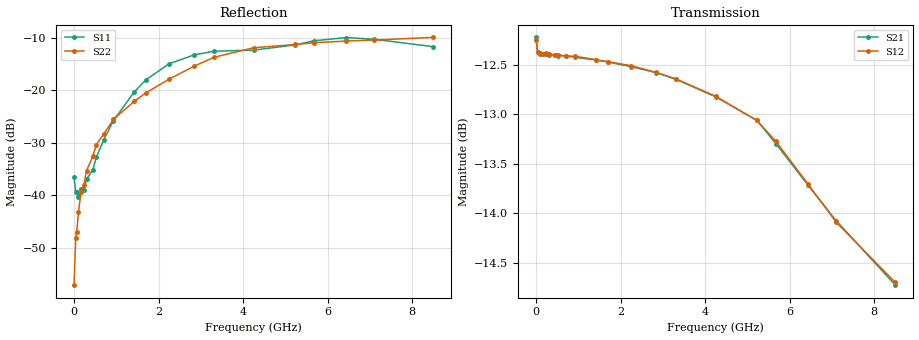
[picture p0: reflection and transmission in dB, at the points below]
! device id: pe43620
! dir: c:\dsa\pe43620\data\pe43620\085c\3p300v\12p00db
! Serial: 1001
! Insertion: A
! Temp: 85C
! VDD: 3.300V
! Attenuation Step: 12.00dB
! IDD: 1.066358e-02mA
! FILE NAME
! DATE 10-22-2008 15:09:18
! CORRECTED  DATA
#  Hz  S  RI  R  50.00
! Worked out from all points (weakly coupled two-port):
!   401 points, 300 kHz to 8.5 GHz, reference 50 ohm
!   highest |S21| = -12.22 dB at 300 kHz (marker M1); lowest = -14.7 dB at 8.5 GHz (marker M2)
!   lowest |S11| = -40.3 dB at 106.5 MHz (marker M3), VSWR 1.02, Z = 50.8 - j0.494 ohm
!   |S11| at or under -10 dB: start of sweep to 6.284 GHz; 6.736 GHz to end of sweep
!   |S22| runs from -57.2 to -9.8 dB; largest |S21 - S12| = 0.0011
!   S11 on the Smith chart (normalised r, x): 300 kHz: 1.03, -0.00; 1.7 GHz: 0.84, -0.17; 5.228 GHz: 0.58, -0.11; 8.5 GHz: 0.61, +0.16
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300000  0.0148 -0.000804  0.2448 -0.000414  0.244 -0.000175  -0.00125 -0.000597
4.27985e7  0.0102 -0.00308  0.2406 -0.00235  0.2408 -0.00241  -0.00241 -0.00307
6.404775e7  0.0101 -0.00359  0.2405 -0.003  0.2405 -0.00304  -0.00242 -0.00373
1.065463e8  0.00839 -0.00486  0.2402 -0.0046  0.2403 -0.00466  -0.00356 -0.00591
1.70294e8  0.0083 -0.00777  0.24 -0.00694  0.2401 -0.00682  -0.00252 -0.0105
2.340418e8  0.00667 -0.00897  0.2399 -0.0091  0.2401 -0.00919  -0.00332 -0.012
2.977895e8  0.00555 -0.013  0.2397 -0.0115  0.2399 -0.0116  -0.00366 -0.0167
4.465343e8  0.00137 -0.0174  0.2392 -0.0172  0.2393 -0.0171  -0.00471 -0.0231
5.315313e8  -0.00345 -0.0229  0.2388 -0.0204  0.239 -0.0204  -0.00772 -0.0294
7.015253e8  -0.00981 -0.032  0.2381 -0.0266  0.2381 -0.0269  -0.00907 -0.0371
9.35267e8  -0.0236 -0.0458  0.2365 -0.0356  0.2368 -0.0356  -0.0167 -0.0504
1.424e9  -0.0573 -0.0776  0.2321 -0.0547  0.2322 -0.0547  -0.0332 -0.071
1.70024e9  -0.0761 -0.1004  0.2288 -0.0652  0.2289 -0.0652  -0.0467 -0.0823
2.252721e9  -0.1072 -0.1443  0.2203 -0.0863  0.2206 -0.0863  -0.0778 -0.1018
2.8477e9  -0.1317 -0.1745  0.209 -0.1074  0.2091 -0.1073  -0.1254 -0.1158
3.315183e9  -0.1509 -0.182  0.1985 -0.1223  0.1987 -0.1222  -0.1567 -0.1356
4.25015e9  -0.1955 -0.1433  0.1744 -0.1476  0.1745 -0.1477  -0.2107 -0.1441
5.227616e9  -0.2575 -0.0865  0.1466 -0.1671  0.1468 -0.1669  -0.2516 -0.109
5.67385e9  -0.2901 -0.0653  0.1301 -0.1729  0.1304 -0.1734  -0.2728 -0.0826
6.438823e9  -0.3177 -0.0335  0.1024 -0.1789  0.1026 -0.1791  -0.2945 -0.028
7.09755e9  -0.3079 0.00344  0.0786 -0.1816  0.0782 -0.1814  -0.3013 0.0258
8.5e9  -0.2291 0.1256  0.0425 -0.1786  0.0424 -0.1792  -0.2974 0.1197
